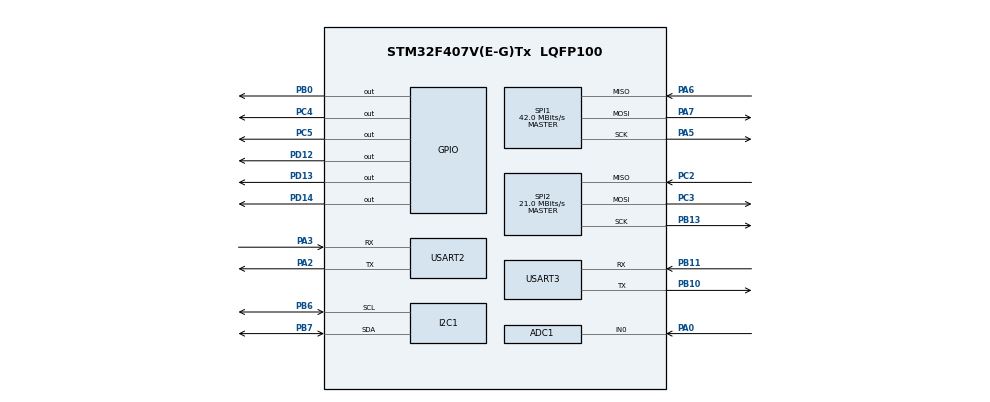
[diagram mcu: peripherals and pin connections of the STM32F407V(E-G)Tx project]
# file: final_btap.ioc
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ADC1.Channel-2\#ChannelRegularConversion=ADC_CHANNEL_0
ADC1.NbrOfConversionFlag=1
ADC1.Rank-2\#ChannelRegularConversion=1
ADC1.SamplingTime-2\#ChannelRegularConversion=ADC_SAMPLETIME_3CYCLES
ADC1.master=1
FREERTOS.Tasks01=defaultTask,24,128,StartDefaultTask,Default,NULL,Dynamic,NULL,NULL
Mcu.Family=STM32F4
Mcu.Name=STM32F407V(E-G)Tx
Mcu.Package=LQFP100
NVIC.PriorityGroup=NVIC_PRIORITYGROUP_4
NVIC.USART2_IRQn=true\:5\:0\:false\:false\:true\:true\:true\:true\:true
NVIC.USART3_IRQn=true\:5\:0\:false\:false\:true\:true\:true\:true\:true
PA0-WKUP.Signal=ADCx_IN0
PA13.Mode=Serial_Wire
PA13.Signal=SYS_JTMS-SWDIO
PA14.Mode=Serial_Wire
PA14.Signal=SYS_JTCK-SWCLK
PA2.Mode=Asynchronous
PA2.Signal=USART2_TX
PA3.Mode=Asynchronous
PA3.Signal=USART2_RX
PA5.Mode=Full_Duplex_Master
PA5.Signal=SPI1_SCK
PA6.Mode=Full_Duplex_Master
PA6.Signal=SPI1_MISO
PA7.Mode=Full_Duplex_Master
PA7.Signal=SPI1_MOSI
PB0.Signal=GPIO_Output
PB10.Mode=Asynchronous
PB10.Signal=USART3_TX
PB11.Mode=Asynchronous
PB11.Signal=USART3_RX
PB13.Mode=Full_Duplex_Master
PB13.Signal=SPI2_SCK
PB6.Mode=I2C
PB6.Signal=I2C1_SCL
PB7.Mode=I2C
PB7.Signal=I2C1_SDA
PC14-OSC32_IN.Mode=LSE-External-Oscillator
PC14-OSC32_IN.Signal=RCC_OSC32_IN
PC15-OSC32_OUT.Mode=LSE-External-Oscillator
PC15-OSC32_OUT.Signal=RCC_OSC32_OUT
PC2.Mode=Full_Duplex_Master
PC2.Signal=SPI2_MISO
PC3.Mode=Full_Duplex_Master
PC3.Signal=SPI2_MOSI
PC4.Signal=GPIO_Output
PC5.Signal=GPIO_Output
PD12.Signal=GPIO_Output
PD13.Signal=GPIO_Output
PD14.Signal=GPIO_Output
PH0-OSC_IN.Mode=HSE-External-Oscillator
PH0-OSC_IN.Signal=RCC_OSC_IN
PH1-OSC_OUT.Mode=HSE-External-Oscillator
PH1-OSC_OUT.Signal=RCC_OSC_OUT
ProjectManager.HeapSize=0x200
ProjectManager.StackSize=0x400
ProjectManager.TargetToolchain=STM32CubeIDE
RCC.48MHZClocksFreq_Value=84000000
RCC.AHBFreq_Value=168000000
RCC.APB1CLKDivider=RCC_HCLK_DIV4
RCC.APB1Freq_Value=42000000
RCC.APB1TimFreq_Value=84000000
RCC.APB2CLKDivider=RCC_HCLK_DIV2
RCC.APB2Freq_Value=84000000
RCC.APB2TimFreq_Value=168000000
RCC.CortexFreq_Value=168000000
RCC.HCLKFreq_Value=168000000
RCC.HSE_VALUE=25000000
RCC.HSI_VALUE=16000000
RCC.PLLM=25
RCC.PLLN=336
RCC.PLLSourceVirtual=RCC_PLLSOURCE_HSE
RCC.SYSCLKFreq_VALUE=168000000
RCC.SYSCLKSource=RCC_SYSCLKSOURCE_PLLCLK
RCC.VCOOutputFreq_Value=336000000
SH.ADCx_IN0.0=ADC1_IN0,IN0
SPI1.CalculateBaudRate=42.0 MBits/s
SPI1.Direction=SPI_DIRECTION_2LINES
SPI1.Mode=SPI_MODE_MASTER
SPI1.VirtualType=VM_MASTER
SPI2.CalculateBaudRate=21.0 MBits/s
SPI2.Direction=SPI_DIRECTION_2LINES
SPI2.Mode=SPI_MODE_MASTER
SPI2.VirtualType=VM_MASTER
USART2.VirtualMode=VM_ASYNC
USART3.VirtualMode=VM_ASYNC
VP_FREERTOS_VS_CMSIS_V2.Mode=CMSIS_V2
board=custom

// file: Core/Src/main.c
/* USER CODE BEGIN Header */
/**
  ******************************************************************************
  * @file           : main.c
  * @brief          : Main program body
  ******************************************************************************
  */
/* USER CODE END Header */
#include "main.h"
#include "cmsis_os.h"

/* USER CODE BEGIN Includes */
#include "logging.h"
#include "adc.h"
#include "freertos.h"
#include "led.h"
#include "spi_w25qxx.h"
#include "i2c_bmp280.h"
#include "i2c_oled_lcd.h"
/* USER CODE END Includes */

ADC_HandleTypeDef hadc1;
I2C_HandleTypeDef hi2c1;
SPI_HandleTypeDef hspi1;
SPI_HandleTypeDef hspi2;
UART_HandleTypeDef huart2;
UART_HandleTypeDef huart3;

osThreadId_t defaultTaskHandle;
const osThreadAttr_t defaultTask_attributes = {
  .name = "defaultTask",
  .stack_size = 128 * 4,
  .priority = (osPriority_t) osPriorityNormal,
};

void SystemClock_Config(void);
static void MX_GPIO_Init(void);
static void MX_USART3_UART_Init(void);
static void MX_USART2_UART_Init(void);
static void MX_ADC1_Init(void);
static void MX_I2C1_Init(void);
static void MX_SPI1_Init(void);
static void MX_SPI2_Init(void);
void StartDefaultTask(void *argument);

/* USER CODE BEGIN PFP */
void MX_FREERTOS_Init(void);
/* USER CODE END PFP */

int main(void)
{
  HAL_Init();
  SystemClock_Config();

  MX_GPIO_Init();
  MX_USART3_UART_Init();
  MX_USART2_UART_Init();
  MX_ADC1_Init();
  MX_I2C1_Init();
  MX_SPI1_Init();
  MX_SPI2_Init();

  /* USER CODE BEGIN 2 */
  // Khởi tạo các module ngoại vi
  Log_Init(&huart2);
  ADC_Init_Module(&hadc1);
  LED_Init();

  LOG_I("=========================================");
  LOG_I(" STM32F407 Boot Successfully at 168 MHz!");
  LOG_I(" FreeRTOS kernel starting...");
  LOG_I("=========================================");

  // Khởi tạo I2C và SPI
  OLED_Init(&hi2c1);
  OLED_ShowString(0, 0, "System Booting...");
  OLED_UpdateScreen();

  BMP280_Init(&hi2c1);
  W25Q_Init(&hspi1);
  /* USER CODE END 2 */

  osKernelInitialize();

  /* USER CODE BEGIN RTOS_THREADS */
  MX_FREERTOS_Init();
  /* USER CODE END RTOS_THREADS */

  defaultTaskHandle = osThreadNew(StartDefaultTask, NULL, &defaultTask_attributes);

  osKernelStart();

  while (1) { }
}

void SystemClock_Config(void)
{
  RCC_OscInitTypeDef RCC_OscInitStruct = {0};
  RCC_ClkInitTypeDef RCC_ClkInitStruct = {0};

  __HAL_RCC_PWR_CLK_ENABLE();
  __HAL_PWR_VOLTAGESCALING_CONFIG(PWR_REGULATOR_VOLTAGE_SCALE1);

  RCC_OscInitStruct.OscillatorType = RCC_OSCILLATORTYPE_HSE;
  RCC_OscInitStruct.HSEState = RCC_HSE_ON;
  RCC_OscInitStruct.PLL.PLLState = RCC_PLL_ON;
  RCC_OscInitStruct.PLL.PLLSource = RCC_PLLSOURCE_HSE;
  RCC_OscInitStruct.PLL.PLLM = 8;     // Đã sửa thành 8 cho thạch anh 8MHz
  RCC_OscInitStruct.PLL.PLLN = 336;
  RCC_OscInitStruct.PLL.PLLP = RCC_PLLP_DIV2;
  RCC_OscInitStruct.PLL.PLLQ = 7;
  if (HAL_RCC_OscConfig(&RCC_OscInitStruct) != HAL_OK) { Error_Handler(); }

  RCC_ClkInitStruct.ClockType = RCC_CLOCKTYPE_HCLK|RCC_CLOCKTYPE_SYSCLK
                              |RCC_CLOCKTYPE_PCLK1|RCC_CLOCKTYPE_PCLK2;
  RCC_ClkInitStruct.SYSCLKSource = RCC_SYSCLKSOURCE_PLLCLK;
  RCC_ClkInitStruct.AHBCLKDivider = RCC_SYSCLK_DIV1;
  RCC_ClkInitStruct.APB1CLKDivider = RCC_HCLK_DIV4;
  RCC_ClkInitStruct.APB2CLKDivider = RCC_HCLK_DIV2;

  if (HAL_RCC_ClockConfig(&RCC_ClkInitStruct, FLASH_LATENCY_5) != HAL_OK) { Error_Handler(); }
}

/* --- CÁC HÀM KHỞI TẠO NGOẠI VI --- */
static void MX_ADC1_Init(void) {
  ADC_ChannelConfTypeDef sConfig = {0};
  hadc1.Instance = ADC1;
  hadc1.Init.ClockPrescaler = ADC_CLOCK_SYNC_PCLK_DIV4;
  hadc1.Init.Resolution = ADC_RESOLUTION_12B;
  hadc1.Init.ScanConvMode = DISABLE;
  hadc1.Init.ContinuousConvMode = DISABLE;
  hadc1.Init.DiscontinuousConvMode = DISABLE;
  hadc1.Init.ExternalTrigConvEdge = ADC_EXTERNALTRIGCONVEDGE_NONE;
  hadc1.Init.ExternalTrigConv = ADC_SOFTWARE_START;
  hadc1.Init.DataAlign = ADC_DATAALIGN_RIGHT;
  hadc1.Init.NbrOfConversion = 1;
  hadc1.Init.DMAContinuousRequests = DISABLE;
  hadc1.Init.EOCSelection = ADC_EOC_SINGLE_CONV;
  if (HAL_ADC_Init(&hadc1) != HAL_OK) Error_Handler();
  sConfig.Channel = ADC_CHANNEL_0;
  sConfig.Rank = 1;
  sConfig.SamplingTime = ADC_SAMPLETIME_3CYCLES;
  if (HAL_ADC_ConfigChannel(&hadc1, &sConfig) != HAL_OK) Error_Handler();
}

static void MX_I2C1_Init(void) {
  hi2c1.Instance = I2C1;
  hi2c1.Init.ClockSpeed = 100000;
  hi2c1.Init.DutyCycle = I2C_DUTYCYCLE_2;
  hi2c1.Init.OwnAddress1 = 0;
  hi2c1.Init.AddressingMode = I2C_ADDRESSINGMODE_7BIT;
  hi2c1.Init.DualAddressMode = I2C_DUALADDRESS_DISABLE;
  hi2c1.Init.OwnAddress2 = 0;
  hi2c1.Init.GeneralCallMode = I2C_GENERALCALL_DISABLE;
  hi2c1.Init.NoStretchMode = I2C_NOSTRETCH_DISABLE;
  if (HAL_I2C_Init(&hi2c1) != HAL_OK) Error_Handler();
}

static void MX_SPI1_Init(void) {
  hspi1.Instance = SPI1;
  hspi1.Init.Mode = SPI_MODE_MASTER;
  hspi1.Init.Direction = SPI_DIRECTION_2LINES;
  hspi1.Init.DataSize = SPI_DATASIZE_8BIT;
  hspi1.Init.CLKPolarity = SPI_POLARITY_LOW;
  hspi1.Init.CLKPhase = SPI_PHASE_1EDGE;
  hspi1.Init.NSS = SPI_NSS_SOFT;
  hspi1.Init.BaudRatePrescaler = SPI_BAUDRATEPRESCALER_2;
  hspi1.Init.FirstBit = SPI_FIRSTBIT_MSB;
  hspi1.Init.TIMode = SPI_TIMODE_DISABLE;
  hspi1.Init.CRCCalculation = SPI_CRCCALCULATION_DISABLE;
  hspi1.Init.CRCPolynomial = 10;
  if (HAL_SPI_Init(&hspi1) != HAL_OK) Error_Handler();
}

static void MX_SPI2_Init(void) {
  hspi2.Instance = SPI2;
  hspi2.Init.Mode = SPI_MODE_MASTER;
  hspi2.Init.Direction = SPI_DIRECTION_2LINES;
  hspi2.Init.DataSize = SPI_DATASIZE_8BIT;
  hspi2.Init.CLKPolarity = SPI_POLARITY_LOW;
  hspi2.Init.CLKPhase = SPI_PHASE_1EDGE;
  hspi2.Init.NSS = SPI_NSS_SOFT;
  hspi2.Init.BaudRatePrescaler = SPI_BAUDRATEPRESCALER_2;
  hspi2.Init.FirstBit = SPI_FIRSTBIT_MSB;
  hspi2.Init.TIMode = SPI_TIMODE_DISABLE;
  hspi2.Init.CRCCalculation = SPI_CRCCALCULATION_DISABLE;
  hspi2.Init.CRCPolynomial = 10;
  if (HAL_SPI_Init(&hspi2) != HAL_OK) Error_Handler();
}

static void MX_USART2_UART_Init(void) {
  huart2.Instance = USART2;
  huart2.Init.BaudRate = 115200;
  huart2.Init.WordLength = UART_WORDLENGTH_8B;
  huart2.Init.StopBits = UART_STOPBITS_1;
  huart2.Init.Parity = UART_PARITY_NONE;
  huart2.Init.Mode = UART_MODE_TX_RX;
  huart2.Init.HwFlowCtl = UART_HWCONTROL_NONE;
  huart2.Init.OverSampling = UART_OVERSAMPLING_16;
  if (HAL_UART_Init(&huart2) != HAL_OK) Error_Handler();
}

static void MX_USART3_UART_Init(void) {
  huart3.Instance = USART3;
  huart3.Init.BaudRate = 115200;
  huart3.Init.WordLength = UART_WORDLENGTH_8B;
  huart3.Init.StopBits = UART_STOPBITS_1;
  huart3.Init.Parity = UART_PARITY_NONE;
  huart3.Init.Mode = UART_MODE_TX_RX;
  huart3.Init.HwFlowCtl = UART_HWCONTROL_NONE;
  huart3.Init.OverSampling = UART_OVERSAMPLING_16;
  if (HAL_UART_Init(&huart3) != HAL_OK) Error_Handler();
}

static void MX_GPIO_Init(void) {
  GPIO_InitTypeDef GPIO_InitStruct = {0};
  __HAL_RCC_GPIOC_CLK_ENABLE();
  __HAL_RCC_GPIOH_CLK_ENABLE();
  __HAL_RCC_GPIOA_CLK_ENABLE();
  __HAL_RCC_GPIOB_CLK_ENABLE();
  __HAL_RCC_GPIOD_CLK_ENABLE();

  HAL_GPIO_WritePin(GPIOC, GPIO_PIN_4|GPIO_PIN_5, GPIO_PIN_RESET);
  HAL_GPIO_WritePin(GPIOB, GPIO_PIN_0, GPIO_PIN_RESET);
  HAL_GPIO_WritePin(GPIOD, GPIO_PIN_12|GPIO_PIN_13|GPIO_PIN_14, GPIO_PIN_RESET);

  GPIO_InitStruct.Pin = GPIO_PIN_4|GPIO_PIN_5;
  GPIO_InitStruct.Mode = GPIO_MODE_OUTPUT_PP;
  GPIO_InitStruct.Pull = GPIO_NOPULL;
  GPIO_InitStruct.Speed = GPIO_SPEED_FREQ_LOW;
  HAL_GPIO_Init(GPIOC, &GPIO_InitStruct);

  GPIO_InitStruct.Pin = GPIO_PIN_0;
  GPIO_InitStruct.Mode = GPIO_MODE_OUTPUT_PP;
  GPIO_InitStruct.Pull = GPIO_NOPULL;
  GPIO_InitStruct.Speed = GPIO_SPEED_FREQ_LOW;
  HAL_GPIO_Init(GPIOB, &GPIO_InitStruct);

  GPIO_InitStruct.Pin = GPIO_PIN_12|GPIO_PIN_13|GPIO_PIN_14;
  GPIO_InitStruct.Mode = GPIO_MODE_OUTPUT_PP;
  GPIO_InitStruct.Pull = GPIO_NOPULL;
  GPIO_InitStruct.Speed = GPIO_SPEED_FREQ_LOW;
  HAL_GPIO_Init(GPIOD, &GPIO_InitStruct);
}

void StartDefaultTask(void *argument)
{
  // KHÔNG ĐIỀU KHIỂN LED Ở ĐÂY NỮA ĐỂ NHƯỜNG QUYỀN CHO TASK SENSOR
  for(;;)
  {
    osDelay(1000); // Chỉ chạy vòng lặp rỗng để giữ Task hoạt động
  }
}

void Error_Handler(void) {
  __disable_irq();
  while (1) { }
}
